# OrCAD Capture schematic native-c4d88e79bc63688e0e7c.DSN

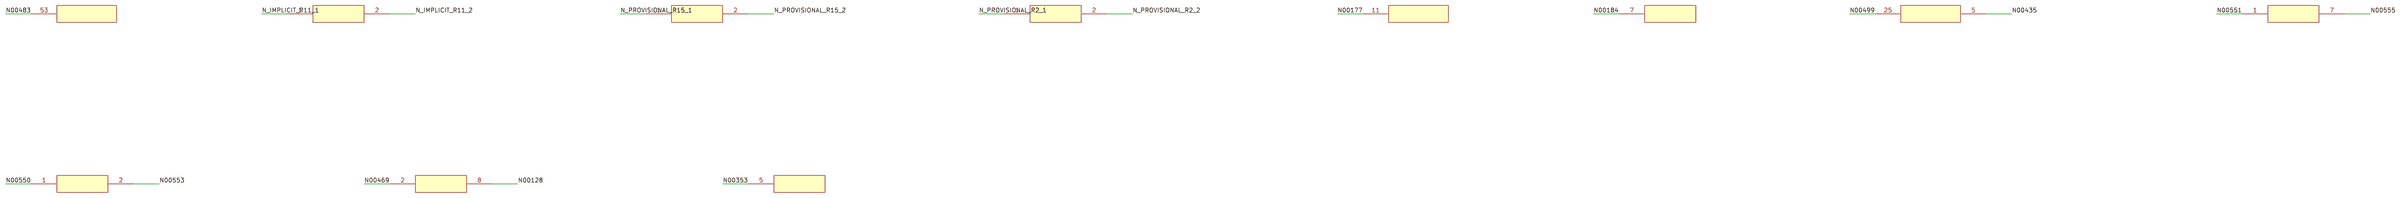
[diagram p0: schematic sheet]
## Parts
P32  CONNECTOR
R2  5.1K
R3  22R
R4  5.1K
R5  0R
R7  10K
R8  10K
R9  100K
R11  10K
R15  1.5K
U580  UNKNOWN

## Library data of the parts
P32 = OBS_P32
R2 = OBS_R2
R3 = OBS_R3
R4 = OBS_R4
R5 = OBS_R5
R7 = OBS_R7
R8 = OBS_R8
R9 = OBS_R9
R11 = OBS_R11
R15 = OBS_R15
U580 = OBS_U580

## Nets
N_IMPLICIT_R11_1: R11.1
N_IMPLICIT_R11_2: R11.2
N_PROVISIONAL_R2_1: R2.1
N_PROVISIONAL_R2_2: R2.2
N_PROVISIONAL_R15_1: R15.1
N_PROVISIONAL_R15_2: R15.2

Not connected (* = marked no-connect by the designer): P32 53; R3 11; R4 7; R5 5 25; R7 1 7; R8 1 2; R9 2 8; U580 5
